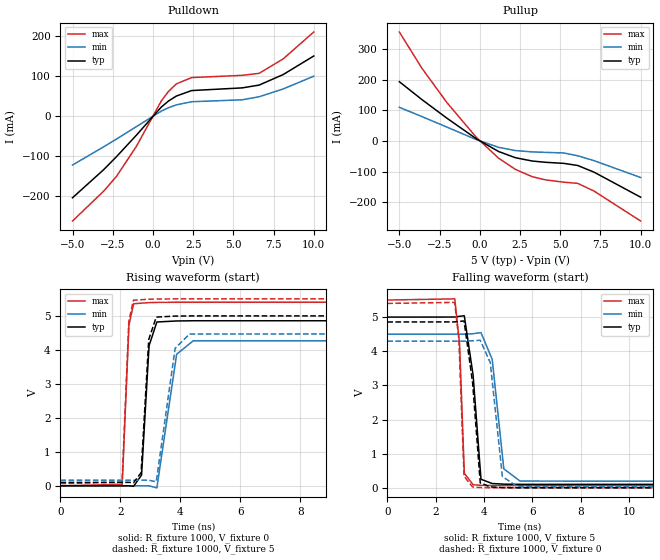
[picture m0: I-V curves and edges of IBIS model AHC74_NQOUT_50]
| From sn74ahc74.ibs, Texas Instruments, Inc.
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[Model]   AHC74_NQOUT_50
Model_type  Output
Vref =   0
Rref =   1000
Cref =   50p
Vmeas =   2.5
| variable   typ   min   max
C_comp   2.21pF   1.75pF   2.76pF
| C_pullup   2.23pF   1.75pF   2.73pF
| C_pulldown   2.20pF   1.86pF   2.76pF
[Temperature Range]   40   100   -40
| Ambient temperature   25   85   -40
[Voltage range]   5   4.5   5.5
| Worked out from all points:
|   slope of the pulldown table from 0 to 0.75 V, typ, clamps not added: 24.2 ohm
|   slope of the pullup table from 0 to 0.75 V, typ, clamps not added: 32.1 ohm
|   rising waveform, R_fixture 1000, V_fixture 0: 20-80 % time 170ps typ, 268ps min, 110ps max; typ from 0 V to 4.86 V
|   falling waveform, R_fixture 1000, V_fixture 5: 20-80 % time 232ps typ, 344ps min, 153ps max; typ from 5 V to 0.101 V
|   rising waveform, R_fixture 1000, V_fixture 5: 20-80 % time 164ps typ, 251ps min, 108ps max; typ from 0.101 V to 5 V
|   falling waveform, R_fixture 1000, V_fixture 0: 20-80 % time 225ps typ, 329ps min, 152ps max; typ from 4.86 V to 0 V
[Pulldown]
| AHC74_NQOUT_50
|   Voltage   I(typ)   I(min)   I(max)
-5V       -203.2mA   -121.7mA   -261.1mA
-3.065V   -133.3mA   -76.34mA   -186.8mA
-2.27V    -101mA     -57.05mA   -150.2mA
-1.02V    -46.97mA   -25.75mA   -74.62mA
510mV     22.36mA    12.39mA    37.2mA
970mV     37.83mA    21.14mA    61.73mA
1.46V     50.19mA    28.2mA     80.49mA
2.405V    63.82mA    36.03mA    96.15mA
5.545V    70.46mA    40.77mA    101.7mA
6.605V    77.49mA    48.42mA    106.7mA
8.095V    103.6mA    67.77mA    142.6mA
10V       149.9mA    99.56mA    209.6mA
[Pullup]
| AHC74_NQOUT_50
|   Voltage   I(typ)   I(min)   I(max)
-5V       193.4mA    109.9mA    355.5mA
-3.6V     135.3mA    79.82mA    237.4mA
-2.035V   74.16mA    45.29mA    124.9mA
-215mV    7.5mA      4.696mA    11.93mA
1.165V    -34.04mA   -20.45mA   -55.72mA
2.21V     -54.21mA   -30.99mA   -92.25mA
3.26V     -65.13mA   -35.31mA   -116.2mA
4.09V     -69.26mA   -36.91mA   -126.6mA
5.215V    -72.73mA   -38.72mA   -134.1mA
6.085V    -79.6mA    -47.92mA   -137.9mA
7.11V     -101.6mA   -64.04mA   -163.3mA
10V       -183mA     -118.8mA   -260.7mA
[Ramp]
| AHC74_NQOUT_50
| variable   typ   min   max
dV/dt_r   2.95/1.82E-10   2.62/2.85E-10   3.26/1.17E-10
dV/dt_f   2.97/2.46E-10   2.63/3.56E-10   3.29/1.61E-10
R_load = 1000
[Rising Waveform]
| AHC74_NQOUT_50
R_fixture =   1000
C_fixture =   0
L_fixture =   0
V_fixture =   0
V_fixture_min = 0
V_fixture_max = 0
|   Time   V(typ)   V(min)   V(max)
0s        1.078nV    1.79nV     663.1pV
2.06ns    -35.65uV   -6.643uV   44.92mV
2.285ns   2.006mV    -139.8uV   4.733V
2.44ns    -13.17mV   -232.4uV   5.356V
2.705ns   316.7mV    1.436mV    5.374V
2.955ns   4.12V      -508uV     5.39V
3.215ns   4.82V      -59.37mV   5.396V
3.875ns   4.85V      3.871V     5.4V
4.425ns   4.856V     4.264V     5.4V
50ns      4.857V     4.295V     5.4V
[Falling Waveform]
| AHC74_NQOUT_50
R_fixture =   1000
C_fixture =   0
L_fixture =   0
V_fixture =   5
V_fixture_min = 4.5
V_fixture_max = 5.5
|   Time   V(typ)   V(min)   V(max)
0s        5V         4.5V       5.5V
2.79ns    5.002V     4.5V       5.534V
2.99ns    5.024V     4.499V     4.207V
3.185ns   5.039V     4.499V     427.4mV
3.55ns    3.295V     4.514V     90.84mV
3.875ns   251.2mV    4.546V     74.02mV
4.34ns    127.3mV    3.76V      68.19mV
4.82ns    108mV      555mV      66.21mV
5.49ns    102.6mV    198.6mV    65.37mV
50ns      100.8mV    165mV      65.08mV
[Rising Waveform]
| AHC74_NQOUT_50
R_fixture =   1000
C_fixture =   0
L_fixture =   0
V_fixture =   5
V_fixture_min = 4.5
V_fixture_max = 5.5
|   Time   V(typ)   V(min)   V(max)
0s        100.8mV    165mV      65.08mV
2.055ns   100.8mV    165mV      108.3mV
2.28ns    102.6mV    164.9mV    4.837V
2.435ns   89.63mV    164.9mV    5.46V
2.69ns    386mV      166.3mV    5.475V
2.945ns   4.308V     164.7mV    5.49V
3.195ns   4.964V     121.4mV    5.496V
3.825ns   4.993V     4.047V     5.5V
4.305ns   4.998V     4.465V     5.5V
50ns      5V         4.5V       5.5V
[Falling Waveform]
| AHC74_NQOUT_50
R_fixture =   1000
C_fixture =   0
L_fixture =   0
V_fixture =   0
V_fixture_min = 0
V_fixture_max = 0
|   Time   V(typ)   V(min)   V(max)
0s        4.857V     4.295V     5.4V
2.785ns   4.859V     4.295V     5.431V
2.96ns    4.875V     4.295V     4.348V
3.175ns   4.886V     4.294V     341mV
3.53ns    3.071V     4.306V     25.42mV
3.845ns   144.4mV    4.322V     9.246mV
4.26ns    28.66mV    3.665V     3.651mV
4.76ns    7.285mV    332.3mV    1.299mV
5.385ns   2.003mV    33.56mV    379.9uV
50ns      -3.415nV   -12.6nV    -290.5pV
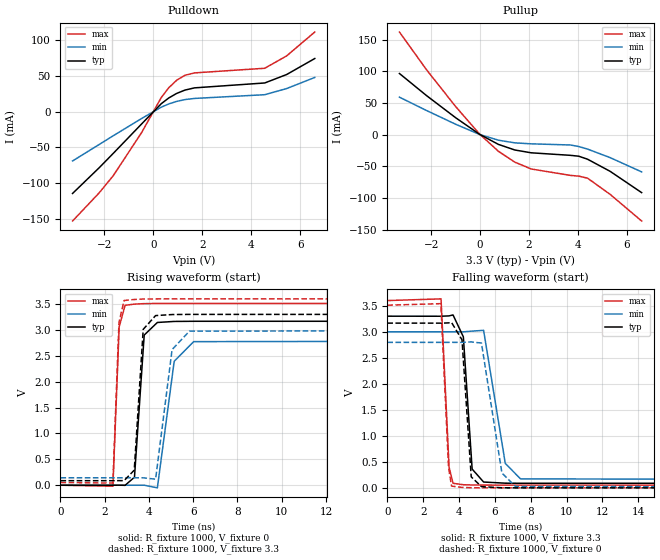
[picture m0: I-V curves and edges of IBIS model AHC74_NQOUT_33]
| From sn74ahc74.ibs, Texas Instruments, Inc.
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[Model]   AHC74_NQOUT_33
Model_type  Output
Vref =   0
Rref =   1000
Cref =   50p
Vmeas =   1.65
| variable   typ   min   max
C_comp   2.43pF   1.80pF   3.26pF
| C_pullup   2.30pF   1.80pF   2.72pF
| C_pulldown   2.56pF   1.89pF   3.26pF
[Temperature Range]   40   100   -40
| Ambient temperature   25   85   -40
[Voltage range]   3.3   3   3.6
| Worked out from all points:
|   slope of the pulldown table from 0 to 0.495 V, typ, clamps not added: 31.8 ohm
|   slope of the pullup table from 0 to 0.495 V, typ, clamps not added: 45.8 ohm
|   rising waveform, R_fixture 1000, V_fixture 0: 20-80 % time 249ps typ, 407ps min, 136ps max; typ from 0 V to 3.17 V
|   falling waveform, R_fixture 1000, V_fixture 3.3: 20-80 % time 315ps typ, 539ps min, 189ps max; typ from 3.3 V to 0.088 V
|   rising waveform, R_fixture 1000, V_fixture 3.3: 20-80 % time 237ps typ, 366ps min, 133ps max; typ from 0.088 V to 3.3 V
|   falling waveform, R_fixture 1000, V_fixture 0: 20-80 % time 297ps typ, 494ps min, 183ps max; typ from 3.17 V to 0 V
[Pulldown]
| AHC74_NQOUT_33
|   Voltage   I(typ)   I(min)   I(max)
-3.3V     -114.4mA   -69.04mA   -152.9mA
-2.22V    -78.8mA    -46.22mA   -113.9mA
-1.635V   -58.39mA   -33.79mA   -89.51mA
-480mV    -17.44mA   -9.793mA   -29.54mA
330mV     11.04mA    6.164mA    19.74mA
635mV     18.98mA    10.63mA    33.32mA
955mV     25.27mA    14.14mA    43.64mA
1.295V    29.94mA    16.67mA    50.63mA
1.685V    33.04mA    18.27mA    53.93mA
4.555V    39.87mA    23.49mA    60.41mA
5.45V     51.66mA    32.05mA    77.66mA
6.6V      73.99mA    47.56mA    111mA
[Pullup]
| AHC74_NQOUT_33
|   Voltage   I(typ)   I(min)   I(max)
-3.3V     96.43mA    59.11mA    161.8mA
-2.19V    61.53mA    38.04mA    102.2mA
-995mV    26.52mA    16.31mA    43.97mA
-15mV     367.5uA    219.4uA    603.7uA
745mV     -15.3mA    -8.685mA   -26.19mA
1.415V    -24.13mA   -12.91mA   -43.25mA
2.085V    -28.58mA   -14.44mA   -54.08mA
3.69V     -32.57mA   -16.26mA   -64.18mA
4.03V     -33.95mA   -18.66mA   -65.36mA
4.39V     -38.7mA    -22.73mA   -68.57mA
5.315V    -57.85mA   -36.24mA   -94.18mA
6.6V      -91.36mA   -58.68mA   -136.1mA
[Ramp]
| AHC74_NQOUT_33
| variable   typ   min   max
dV/dt_r   1.93/2.65E-10   1.71/4.14E-10   2.13/1.41E-10
dV/dt_f   1.96/3.30E-10   1.74/5.52E-10   2.15/2.01E-10
R_load = 1000
[Rising Waveform]
| AHC74_NQOUT_33
R_fixture =   1000
C_fixture =   0
L_fixture =   0
V_fixture =   0
V_fixture_min = 0
V_fixture_max = 0
|   Time   V(typ)   V(min)   V(max)
0s        938.3pV    1.562nV    526.1pV
2.37ns    -237.3uV   14.87uV    -18.68mV
2.655ns   1.182mV    -88.01uV   3.061V
2.92ns    -1.91mV    -215.3uV   3.475V
3.345ns   154.7mV    859.4uV    3.499V
3.785ns   2.901V     626.5uV    3.508V
4.38ns    3.144V     -50.45mV   3.511V
5.14ns    3.164V     2.394V     3.511V
6.02ns    3.167V     2.774V     3.511V
50ns      3.167V     2.797V     3.511V
[Falling Waveform]
| AHC74_NQOUT_33
R_fixture =   1000
C_fixture =   0
L_fixture =   0
V_fixture =   3.3
V_fixture_min = 3
V_fixture_max = 3.6
|   Time   V(typ)   V(min)   V(max)
0s        3.3V       3V         3.6V
2.995ns   3.299V     3V         3.633V
3.445ns   3.306V     3V         396.6mV
3.665ns   3.324V     3V         87.5mV
4.24ns    2.903V     2.999V     59.93mV
4.73ns    361.4mV    3.013V     55.03mV
5.37ns    112mV      3.028V     53.23mV
6.58ns    89.52mV    469.1mV    52.62mV
7.43ns    88.27mV    172.7mV    52.57mV
50ns      87.98mV    143.4mV    52.56mV
[Rising Waveform]
| AHC74_NQOUT_33
R_fixture =   1000
C_fixture =   0
L_fixture =   0
V_fixture =   3.3
V_fixture_min = 3
V_fixture_max = 3.6
|   Time   V(typ)   V(min)   V(max)
0s        87.98mV    143.4mV    52.56mV
2.37ns    87.83mV    143.4mV    42.31mV
2.645ns   89.08mV    143.3mV    3.148V
2.875ns   88.53mV    143.3mV    3.568V
3.335ns   291.1mV    144.2mV    3.588V
3.74ns    3.011V     143.6mV    3.597V
4.3ns     3.277V     116.8mV    3.599V
5.045ns   3.297V     2.62V      3.6V
5.83ns    3.3V       2.977V     3.6V
50ns      3.3V       3V         3.6V
[Falling Waveform]
| AHC74_NQOUT_33
R_fixture =   1000
C_fixture =   0
L_fixture =   0
V_fixture =   0
V_fixture_min = 0
V_fixture_max = 0
|   Time   V(typ)   V(min)   V(max)
0s        3.167V     2.797V     3.511V
2.985ns   3.166V     2.797V     3.541V
3.415ns   3.171V     2.797V     396.5mV
3.58ns    3.18V      2.797V     33.81mV
4.165ns   2.846V     2.797V     8.084mV
4.68ns    211mV      2.805V     2.567mV
5.25ns    23.27mV    2.784V     819.8uV
6.39ns    1.733mV    285.9mV    92.12uV
7.145ns   408uV      27.2mV     22.25uV
50ns      -8.421nV   -30.22nV   -5.038nV
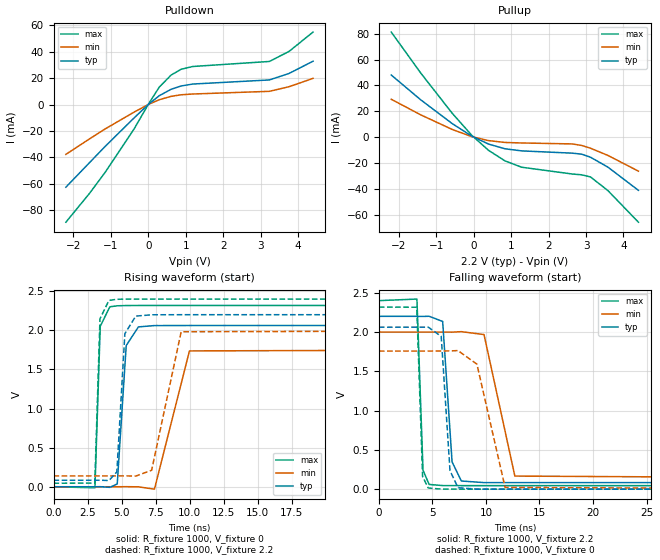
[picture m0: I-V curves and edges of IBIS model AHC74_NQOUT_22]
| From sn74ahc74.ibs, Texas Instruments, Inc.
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[Model]   AHC74_NQOUT_22
Model_type  Output
Vref =   0
Rref =   1000
Cref =   50p
Vmeas =   1.1
| variable   typ   min   max
C_comp   2.56pF   1.81pF   3.65pF
| C_pullup   2.32pF   1.81pF   2.69pF
| C_pulldown   2.81pF   1.92pF   3.65pF
[Temperature Range]   40   100   -40
| Ambient temperature   25   85   -40
[Voltage range]   2.2   2   2.4
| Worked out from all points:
|   slope of the pulldown table from 0 to 0.33 V, typ, clamps not added: 45.1 ohm
|   slope of the pullup table from 0 to 0.33 V, typ, clamps not added: 72.7 ohm
|   rising waveform, R_fixture 1000, V_fixture 0: 20-80 % time 393ps typ, 843ps min, 206ps max; typ from 0 V to 2.06 V
|   falling waveform, R_fixture 1000, V_fixture 2.2: 20-80 % time 523ps typ, 1.03ns min, 246ps max; typ from 2.2 V to 0.083 V
|   rising waveform, R_fixture 1000, V_fixture 2.2: 20-80 % time 362ps typ, 678ps min, 201ps max; typ from 0.083 V to 2.2 V
|   falling waveform, R_fixture 1000, V_fixture 0: 20-80 % time 497ps typ, 1.16ns min, 236ps max; typ from 2.06 V to 0 V
[Pulldown]
| AHC74_NQOUT_22
|   Voltage   I(typ)   I(min)   I(max)
-2.2V     -62.5mA    -37.71mA   -88.97mA
-1.57V    -43.98mA   -26.01mA   -67.23mA
-1.155V   -31.79mA   -18.52mA   -51.42mA
-380mV    -10.19mA   -5.783mA   -18.54mA
10mV      264.1uA    144.1uA    536.1uA
295mV     6.674mA    3.624mA    13.19mA
610mV     11.5mA     6.157mA    22.25mA
875mV     13.99mA    7.339mA    26.61mA
1.185V    15.46mA    7.929mA    28.73mA
3.235V    18.57mA    9.958mA    32.54mA
3.76V     23.49mA    13.45mA    40.15mA
4.4V      32.72mA    19.75mA    54.74mA
[Pullup]
| AHC74_NQOUT_22
|   Voltage   I(typ)   I(min)   I(max)
-2.2V     48mA       29.29mA    81.17mA
-1.415V   28.89mA    17.28mA    49.61mA
-575mV    10.55mA    6.012mA    18.55mA
-50mV     801.5uA    426.7uA    1.459mA
395mV     -5.276mA   -2.621mA   -10.1mA
835mV     -8.961mA   -4.058mA   -18.26mA
1.28V     -10.57mA   -4.458mA   -23.18mA
2.635V    -12.33mA   -5.195mA   -28.44mA
2.885V    -13.1mA    -6.389mA   -29.05mA
3.12V     -15.48mA   -8.519mA   -30.68mA
3.585V    -23.12mA   -14.08mA   -41.24mA
4.4V      -41.05mA   -26.22mA   -65.64mA
[Ramp]
| AHC74_NQOUT_22
| variable   typ   min   max
dV/dt_r   1.27/4.09E-10   1.09/8.61E-10   1.41/2.19E-10
dV/dt_f   1.29/5.39E-10   1.14/1.06E-09   1.44/2.59E-10
R_load = 1000
[Rising Waveform]
| AHC74_NQOUT_22
R_fixture =   1000
C_fixture =   0
L_fixture =   0
V_fixture =   0
V_fixture_min = 0
V_fixture_max = 0
|   Time   V(typ)   V(min)   V(max)
0s        865.9pV    1.52nV     445.3pV
3.045ns   -195.3uV   39.36uV    -13.36mV
3.435ns   601.3uV    7.159uV    2.052V
4.14ns    -7.547mV   -116.6uV   2.301V
4.685ns   35.78mV    8.076uV    2.314V
5.345ns   1.806V     824uV      2.317V
6.24ns    2.044V     -949.7uV   2.318V
7.42ns    2.061V     -30.87mV   2.318V
9.995ns   2.062V     1.737V     2.318V
50ns      2.062V     1.758V     2.318V
[Falling Waveform]
| AHC74_NQOUT_22
R_fixture =   1000
C_fixture =   0
L_fixture =   0
V_fixture =   2.2
V_fixture_min = 2
V_fixture_max = 2.4
|   Time   V(typ)   V(min)   V(max)
0s        2.2V       2V         2.4V
3.55ns    2.2V       2V         2.42V
4.12ns    2.199V     2V         241.3mV
4.69ns    2.201V     2V         59.98mV
5.955ns   2.135V     2V         45.75mV
6.835ns   346.8mV    1.999V     45.07mV
7.7ns     103.9mV    2.005V     44.95mV
9.82ns    83.66mV    1.968V     44.92mV
12.7ns    83.34mV    166.6mV    44.92mV
50ns      83.34mV    138.6mV    44.92mV
[Rising Waveform]
| AHC74_NQOUT_22
R_fixture =   1000
C_fixture =   0
L_fixture =   0
V_fixture =   2.2
V_fixture_min = 2
V_fixture_max = 2.4
|   Time   V(typ)   V(min)   V(max)
0s        83.34mV    138.6mV    44.92mV
3.035ns   83.28mV    138.6mV    46.65mV
3.415ns   83.98mV    138.6mV    2.148V
4.075ns   78.84mV    138.6mV    2.383V
4.655ns   189.9mV    138.9mV    2.397V
5.245ns   1.957V     139mV      2.399V
6.045ns   2.182V     136.5mV    2.4V
7.215ns   2.199V     211.3mV    2.4V
9.385ns   2.2V       1.982V     2.4V
50ns      2.2V       2V         2.4V
[Falling Waveform]
| AHC74_NQOUT_22
R_fixture =   1000
C_fixture =   0
L_fixture =   0
V_fixture =   0
V_fixture_min = 0
V_fixture_max = 0
|   Time   V(typ)   V(min)   V(max)
0s        2.062V     1.758V     2.318V
3.535ns   2.062V     1.758V     2.316V
4.08ns    2.062V     1.758V     162.3mV
4.605ns   2.063V     1.758V     14.91mV
5.82ns    1.945V     1.759V     918.5uV
6.64ns    235.5mV    1.76V      190.1uV
7.39ns    18.73mV    1.764V     46.26uV
9.155ns   530.8uV    1.591V     1.886uV
11.79ns   5.295uV    22.02mV    49.12nV
50ns      -23.3nV    -9.357nV   -3.774nV
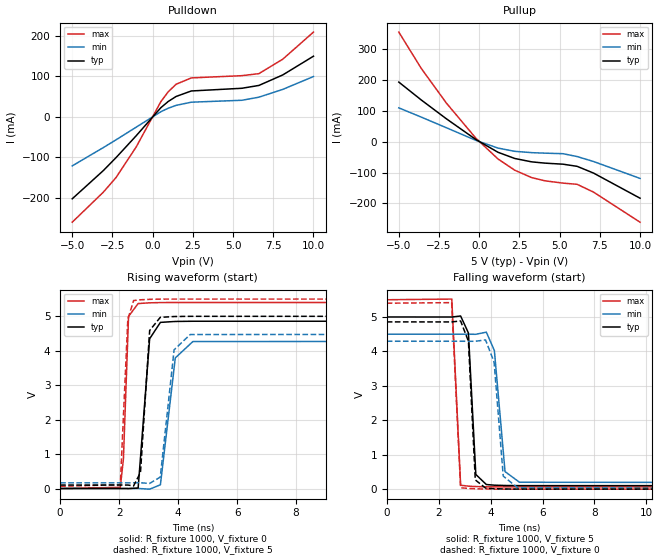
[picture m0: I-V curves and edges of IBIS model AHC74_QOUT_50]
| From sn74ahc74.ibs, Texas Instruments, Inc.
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[Model]   AHC74_QOUT_50
Model_type  Output
Vref =   0
Rref =   1000
Cref =   50p
Vmeas =   2.5
| variable   typ   min   max
C_comp   2.14pF   1.66pF   2.79pF
| C_pullup   2.28pF   1.76pF   2.79pF
| C_pulldown   2.01pF   1.66pF   2.42pF
[Temperature Range]   40   100   -40
| Ambient temperature   25   85   -40
[Voltage range]   5   4.5   5.5
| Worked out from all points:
|   slope of the pulldown table from 0 to 0.75 V, typ, clamps not added: 24.2 ohm
|   slope of the pullup table from 0 to 0.75 V, typ, clamps not added: 32.1 ohm
|   rising waveform, R_fixture 1000, V_fixture 0: 20-80 % time 190ps typ, 285ps min, 114ps max; typ from 0 V to 4.86 V
|   falling waveform, R_fixture 1000, V_fixture 5: 20-80 % time 168ps typ, 251ps min, 101ps max; typ from 5 V to 0.101 V
|   rising waveform, R_fixture 1000, V_fixture 5: 20-80 % time 184ps typ, 272ps min, 113ps max; typ from 0.101 V to 5 V
|   falling waveform, R_fixture 1000, V_fixture 0: 20-80 % time 155ps typ, 234ps min, 99.9ps max; typ from 4.86 V to 0 V
[Pulldown]
| AHC74_QOUT_50
|   Voltage   I(typ)   I(min)   I(max)
-5V       -203.2mA   -121.7mA   -261.1mA
-3.065V   -133.3mA   -76.34mA   -186.8mA
-2.27V    -101mA     -57.05mA   -150.2mA
-1.02V    -46.97mA   -25.75mA   -74.62mA
510mV     22.36mA    12.39mA    37.2mA
970mV     37.83mA    21.14mA    61.73mA
1.46V     50.19mA    28.2mA     80.49mA
2.405V    63.82mA    36.03mA    96.15mA
5.545V    70.46mA    40.77mA    101.7mA
6.605V    77.49mA    48.42mA    106.7mA
8.09V     103.5mA    67.7mA     142.5mA
10V       149.9mA    99.56mA    209.6mA
[Pullup]
| AHC74_QOUT_50
|   Voltage   I(typ)   I(min)   I(max)
-5V       193.4mA    109.9mA    355.5mA
-3.6V     135.3mA    79.82mA    237.4mA
-2.035V   74.16mA    45.29mA    124.9mA
-215mV    7.5mA      4.696mA    11.93mA
1.165V    -34.04mA   -20.45mA   -55.72mA
2.21V     -54.21mA   -30.99mA   -92.25mA
3.26V     -65.13mA   -35.31mA   -116.2mA
4.09V     -69.26mA   -36.91mA   -126.6mA
5.215V    -72.73mA   -38.72mA   -134.1mA
6.085V    -79.6mA    -47.92mA   -137.9mA
7.11V     -101.6mA   -64.04mA   -163.3mA
10V       -183mA     -118.8mA   -260.7mA
[Ramp]
| AHC74_QOUT_50
| variable   typ   min   max
dV/dt_r   2.94/2.05E-10   2.61/2.91E-10   3.26/1.17E-10
dV/dt_f   2.98/1.81E-10   2.64/2.64E-10   3.30/1.06E-10
R_load = 1000
[Rising Waveform]
| AHC74_QOUT_50
R_fixture =   1000
C_fixture =   0
L_fixture =   0
V_fixture =   0
V_fixture_min = 0
V_fixture_max = 0
|   Time   V(typ)   V(min)   V(max)
0s        1.078nV    1.79nV     663.1pV
2.04ns    260.4uV    -22.62uV   35.2mV
2.145ns   1.343mV    -52.69uV   850.2mV
2.32ns    -1.037mV   -99.99uV   4.997V
2.645ns   14.86mV    2.114mV    5.37V
3.035ns   4.348V     -18.73mV   5.391V
3.4ns     4.823V     109mV      5.398V
3.905ns   4.85V      3.792V     5.4V
4.5ns     4.856V     4.266V     5.4V
50ns      4.857V     4.295V     5.4V
[Falling Waveform]
| AHC74_QOUT_50
R_fixture =   1000
C_fixture =   0
L_fixture =   0
V_fixture =   5
V_fixture_min = 4.5
V_fixture_max = 5.5
|   Time   V(typ)   V(min)   V(max)
0s        5V         4.5V       5.5V
2.505ns   4.999V     4.5V       5.52V
2.845ns   5.028V     4.5V       113.9mV
3.145ns   4.536V     4.499V     87.5mV
3.43ns    427mV      4.497V     75.57mV
3.835ns   134.8mV    4.559V     69.08mV
4.145ns   115.7mV    4.025V     67.12mV
4.555ns   106.7mV    510.9mV    65.96mV
5.11ns    102.7mV    200.8mV    65.37mV
50ns      100.8mV    165mV      65.08mV
[Rising Waveform]
| AHC74_QOUT_50
R_fixture =   1000
C_fixture =   0
L_fixture =   0
V_fixture =   5
V_fixture_min = 4.5
V_fixture_max = 5.5
|   Time   V(typ)   V(min)   V(max)
0s        100.8mV    165mV      65.08mV
2.04ns    101.1mV    165mV      109mV
2.295ns   101mV      165mV      4.912V
2.49ns    74.78mV    165.6mV    5.457V
2.725ns   469mV      167.2mV    5.479V
3.035ns   4.587V     147.8mV    5.492V
3.395ns   4.969V     331mV      5.498V
3.865ns   4.993V     4.028V     5.5V
4.41ns    4.999V     4.47V      5.5V
50ns      5V         4.5V       5.5V
[Falling Waveform]
| AHC74_QOUT_50
R_fixture =   1000
C_fixture =   0
L_fixture =   0
V_fixture =   0
V_fixture_min = 0
V_fixture_max = 0
|   Time   V(typ)   V(min)   V(max)
0s        4.857V     4.295V     5.4V
2.5ns     4.856V     4.295V     5.416V
2.845ns   4.884V     4.295V     40.54mV
3.145ns   4.295V     4.294V     21.39mV
3.41ns    268.4mV    4.294V     10.69mV
3.805ns   32.42mV    4.334V     4.249mV
4.135ns   13.61mV    3.685V     2.11mV
4.485ns   6.269mV    379.7mV    1.041mV
5.05ns    1.979mV    35.76mV    345uV
50ns      -7.26nV    -3.541nV   -6.261nV
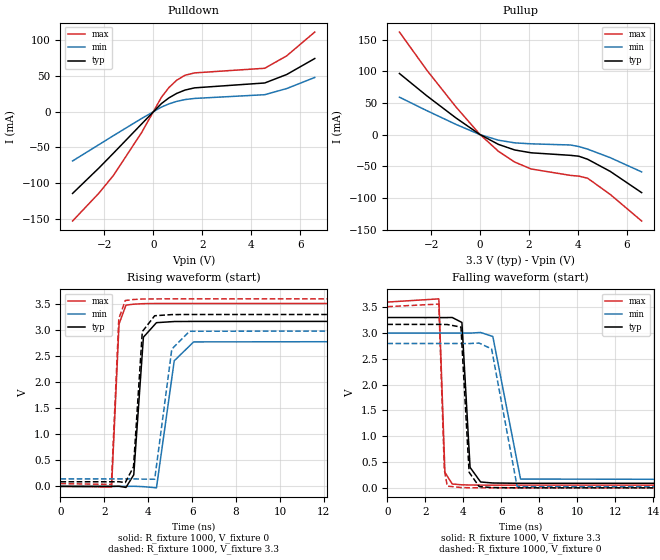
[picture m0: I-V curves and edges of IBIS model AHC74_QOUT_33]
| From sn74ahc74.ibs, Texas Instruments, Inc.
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[Model]   AHC74_QOUT_33
Model_type  Output
Vref =   0
Rref =   1000
Cref =   50p
Vmeas =   1.65
| variable   typ   min   max
C_comp   2.33pF   1.80pF   2.84pF
| C_pullup   2.35pF   1.80pF   2.78pF
| C_pulldown   2.32pF   1.90pF   2.84pF
[Temperature Range]   40   100   -40
| Ambient temperature   25   85   -40
[Voltage range]   3.3   3   3.6
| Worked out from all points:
|   slope of the pulldown table from 0 to 0.495 V, typ, clamps not added: 31.8 ohm
|   slope of the pullup table from 0 to 0.495 V, typ, clamps not added: 45.8 ohm
|   rising waveform, R_fixture 1000, V_fixture 0: 20-80 % time 266ps typ, 438ps min, 155ps max; typ from 0 V to 3.17 V
|   falling waveform, R_fixture 1000, V_fixture 3.3: 20-80 % time 226ps typ, 391ps min, 130ps max; typ from 3.3 V to 0.088 V
|   rising waveform, R_fixture 1000, V_fixture 3.3: 20-80 % time 252ps typ, 393ps min, 151ps max; typ from 0.088 V to 3.3 V
|   falling waveform, R_fixture 1000, V_fixture 0: 20-80 % time 218ps typ, 359ps min, 128ps max; typ from 3.17 V to 0 V
[Pulldown]
| AHC74_QOUT_33
|   Voltage   I(typ)   I(min)   I(max)
-3.3V     -114.4mA   -69.04mA   -152.9mA
-2.22V    -78.8mA    -46.22mA   -113.9mA
-1.635V   -58.39mA   -33.79mA   -89.51mA
-480mV    -17.44mA   -9.793mA   -29.54mA
330mV     11.04mA    6.164mA    19.74mA
635mV     18.98mA    10.63mA    33.32mA
955mV     25.27mA    14.14mA    43.64mA
1.295V    29.94mA    16.67mA    50.63mA
1.685V    33.04mA    18.27mA    53.93mA
4.555V    39.87mA    23.49mA    60.41mA
5.45V     51.66mA    32.05mA    77.66mA
6.6V      73.99mA    47.56mA    111mA
[Pullup]
| AHC74_QOUT_33
|   Voltage   I(typ)   I(min)   I(max)
-3.3V     96.43mA    59.11mA    161.8mA
-2.19V    61.53mA    38.04mA    102.2mA
-995mV    26.52mA    16.31mA    43.97mA
-15mV     367.5uA    219.4uA    603.7uA
745mV     -15.3mA    -8.685mA   -26.19mA
1.415V    -24.13mA   -12.91mA   -43.25mA
2.085V    -28.58mA   -14.44mA   -54.08mA
3.69V     -32.57mA   -16.26mA   -64.18mA
4.03V     -33.95mA   -18.66mA   -65.36mA
4.39V     -38.7mA    -22.73mA   -68.57mA
5.315V    -57.85mA   -36.24mA   -94.18mA
6.6V      -91.36mA   -58.68mA   -136.1mA
[Ramp]
| AHC74_QOUT_33
| variable   typ   min   max
dV/dt_r   1.93/2.83E-10   1.71/4.48E-10   2.13/1.67E-10
dV/dt_f   1.97/2.39E-10   1.75/4.02E-10   2.17/1.39E-10
R_load = 1000
[Rising Waveform]
| AHC74_QOUT_33
R_fixture =   1000
C_fixture =   0
L_fixture =   0
V_fixture =   0
V_fixture_min = 0
V_fixture_max = 0
|   Time   V(typ)   V(min)   V(max)
0s        923.7pV    1.562nV    526.1pV
2.33ns    26.15uV    -21.4uV    -12.02mV
2.67ns    2.292mV    -84.36uV   3.118V
2.985ns   -20.35mV   226.7uV    3.48V
3.34ns    221.6mV    1.707mV    3.498V
3.78ns    2.864V     -5.473mV   3.508V
4.375ns   3.143V     -28.42mV   3.511V
5.185ns   3.165V     2.411V     3.511V
6.07ns    3.167V     2.774V     3.511V
50ns      3.167V     2.797V     3.511V
[Falling Waveform]
| AHC74_QOUT_33
R_fixture =   1000
C_fixture =   0
L_fixture =   0
V_fixture =   3.3
V_fixture_min = 3
V_fixture_max = 3.6
|   Time   V(typ)   V(min)   V(max)
0s        3.3V       3V         3.6V
2.715ns   3.3V       3V         3.662V
3.035ns   3.299V     3V         299.7mV
3.42ns    3.301V     3V         74.56mV
3.93ns    3.205V     3V         58.57mV
4.36ns    397mV      2.998V     54.9mV
4.915ns   113.8mV    3.011V     53.32mV
5.56ns    93.83mV    2.933V     52.77mV
7.02ns    88.31mV    170.3mV    52.57mV
50ns      87.98mV    143.4mV    52.56mV
[Rising Waveform]
| AHC74_QOUT_33
R_fixture =   1000
C_fixture =   0
L_fixture =   0
V_fixture =   3.3
V_fixture_min = 3
V_fixture_max = 3.6
|   Time   V(typ)   V(min)   V(max)
0s        87.98mV    143.4mV    52.56mV
2.32ns    88mV       143.4mV    37.36mV
2.66ns    89.72mV    143.3mV    3.22V
2.955ns   73.33mV    143.6mV    3.568V
3.33ns    375.8mV    144.4mV    3.588V
3.73ns    2.972V     138.8mV    3.597V
4.295ns   3.276V     137.1mV    3.599V
5.075ns   3.298V     2.635V     3.6V
5.88ns    3.3V       2.978V     3.6V
50ns      3.3V       3V         3.6V
[Falling Waveform]
| AHC74_QOUT_33
R_fixture =   1000
C_fixture =   0
L_fixture =   0
V_fixture =   0
V_fixture_min = 0
V_fixture_max = 0
|   Time   V(typ)   V(min)   V(max)
0s        3.167V     2.797V     3.511V
2.715ns   3.167V     2.797V     3.561V
3.005ns   3.166V     2.797V     346.5mV
3.16ns    3.165V     2.797V     33.61mV
3.88ns    3.115V     2.797V     6.309mV
4.31ns    301.8mV    2.796V     2.473mV
4.84ns    24.7mV     2.805V     851.6uV
5.495ns   5.432mV    2.692V     240.3uV
6.84ns    401.8uV    25.87mV    19.02uV
50ns      -8.616nV   -23.89nV   -6.276nV
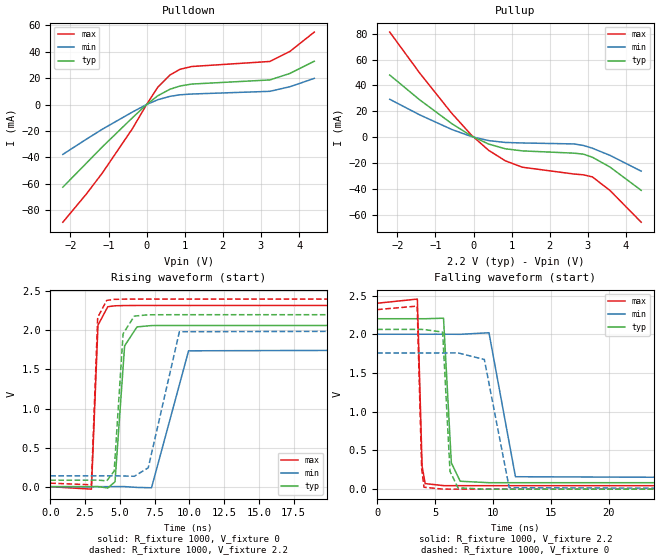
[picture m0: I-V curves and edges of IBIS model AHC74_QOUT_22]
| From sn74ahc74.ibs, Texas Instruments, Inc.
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[Model]   AHC74_QOUT_22
Model_type  Output
Vref =   0
Rref =   1000
Cref =   50p
Vmeas =   1.1
| variable   typ   min   max
C_comp   2.46pF   1.82pF   3.12pF
| C_pullup   2.38pF   1.82pF   2.75pF
| C_pulldown   2.54pF   1.96pF   3.12pF
[Temperature Range]   40   100   -40
| Ambient temperature   25   85   -40
[Voltage range]   2.2   2   2.4
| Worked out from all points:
|   slope of the pulldown table from 0 to 0.33 V, typ, clamps not added: 45.1 ohm
|   slope of the pullup table from 0 to 0.33 V, typ, clamps not added: 72.7 ohm
|   rising waveform, R_fixture 1000, V_fixture 0: 20-80 % time 425ps typ, 897ps min, 221ps max; typ from 0 V to 2.06 V
|   falling waveform, R_fixture 1000, V_fixture 2.2: 20-80 % time 368ps typ, 722ps min, 176ps max; typ from 2.2 V to 0.083 V
|   rising waveform, R_fixture 1000, V_fixture 2.2: 20-80 % time 391ps typ, 746ps min, 212ps max; typ from 0.083 V to 2.2 V
|   falling waveform, R_fixture 1000, V_fixture 0: 20-80 % time 350ps typ, 734ps min, 173ps max; typ from 2.06 V to 0 V
[Pulldown]
| AHC74_QOUT_22
|   Voltage   I(typ)   I(min)   I(max)
-2.2V     -62.5mA    -37.71mA   -88.97mA
-1.57V    -43.98mA   -26.01mA   -67.23mA
-1.155V   -31.79mA   -18.52mA   -51.42mA
-380mV    -10.19mA   -5.783mA   -18.54mA
10mV      264.1uA    144.1uA    536.1uA
295mV     6.674mA    3.624mA    13.19mA
610mV     11.5mA     6.157mA    22.25mA
875mV     13.99mA    7.339mA    26.61mA
1.185V    15.46mA    7.929mA    28.73mA
3.235V    18.57mA    9.958mA    32.54mA
3.76V     23.49mA    13.45mA    40.15mA
4.4V      32.72mA    19.75mA    54.74mA
[Pullup]
| AHC74_QOUT_22
|   Voltage   I(typ)   I(min)   I(max)
-2.2V     48mA       29.29mA    81.17mA
-1.415V   28.89mA    17.28mA    49.61mA
-575mV    10.55mA    6.012mA    18.55mA
-50mV     801.5uA    426.7uA    1.459mA
395mV     -5.276mA   -2.621mA   -10.1mA
835mV     -8.961mA   -4.058mA   -18.26mA
1.28V     -10.57mA   -4.458mA   -23.18mA
2.635V    -12.33mA   -5.195mA   -28.44mA
2.885V    -13.1mA    -6.389mA   -29.05mA
3.12V     -15.48mA   -8.519mA   -30.68mA
3.585V    -23.12mA   -14.08mA   -41.24mA
4.4V      -41.05mA   -26.22mA   -65.64mA
[Ramp]
| AHC74_QOUT_22
| variable   typ   min   max
dV/dt_r   1.27/4.40E-10   1.09/9.15E-10   1.41/2.32E-10
dV/dt_f   1.31/3.86E-10   1.15/7.43E-10   1.45/1.85E-10
R_load = 1000
[Rising Waveform]
| AHC74_QOUT_22
R_fixture =   1000
C_fixture =   0
L_fixture =   0
V_fixture =   0
V_fixture_min = 0
V_fixture_max = 0
|   Time   V(typ)   V(min)   V(max)
0s        865.9pV    1.52nV     445.3pV
2.96ns    -27.68uV   -7.134uV   -31.91mV
3.43ns    1.392mV    -31.9uV    2.066V
4.135ns   -17.11mV   -23.36uV   2.302V
4.655ns   62.64mV    752.4uV    2.314V
5.345ns   1.801V     772.1uV    2.317V
6.235ns   2.044V     -9.514mV   2.318V
7.28ns    2.061V     -14.27mV   2.318V
9.945ns   2.062V     1.738V     2.318V
50ns      2.062V     1.758V     2.318V
[Falling Waveform]
| AHC74_QOUT_22
R_fixture =   1000
C_fixture =   0
L_fixture =   0
V_fixture =   2.2
V_fixture_min = 2
V_fixture_max = 2.4
|   Time   V(typ)   V(min)   V(max)
0s        2.2V       2V         2.4V
3.47ns    2.2V       2V         2.454V
3.88ns    2.2V       2V         297.1mV
4.145ns   2.2V       2V         72.01mV
5.73ns    2.207V     2V         45.78mV
6.405ns   340.1mV    2V         45.15mV
7.17ns    102.2mV    1.999V     44.97mV
9.655ns   83.49mV    2.019V     44.92mV
11.94ns   83.34mV    160.6mV    44.92mV
50ns      83.34mV    138.6mV    44.92mV
[Rising Waveform]
| AHC74_QOUT_22
R_fixture =   1000
C_fixture =   0
L_fixture =   0
V_fixture =   2.2
V_fixture_min = 2
V_fixture_max = 2.4
|   Time   V(typ)   V(min)   V(max)
0s        83.34mV    138.6mV    44.92mV
2.955ns   83.37mV    138.6mV    24.2mV
3.41ns    84.12mV    138.6mV    2.166V
4.06ns    74.08mV    138.6mV    2.383V
4.595ns   199.7mV    139mV      2.396V
5.235ns   1.956V     137.3mV    2.399V
6.04ns    2.182V     132.7mV    2.4V
7.045ns   2.199V     241.3mV    2.4V
9.285ns   2.2V       1.982V     2.4V
50ns      2.2V       2V         2.4V
[Falling Waveform]
| AHC74_QOUT_22
R_fixture =   1000
C_fixture =   0
L_fixture =   0
V_fixture =   0
V_fixture_min = 0
V_fixture_max = 0
|   Time   V(typ)   V(min)   V(max)
0s        2.062V     1.758V     2.318V
3.455ns   2.062V     1.758V     2.363V
3.84ns    2.062V     1.758V     268.7mV
4.045ns   2.061V     1.758V     25.11mV
5.655ns   2.027V     1.758V     885uV
6.29ns    230.5mV    1.758V     261.6uV
6.98ns    17.76mV    1.759V     71.24uV
9.255ns   202.7uV    1.674V     1.234uV
11.4ns    4.925uV    18.99mV    48.7nV
50ns      -18.78nV   5.685nV    -3.691nV
